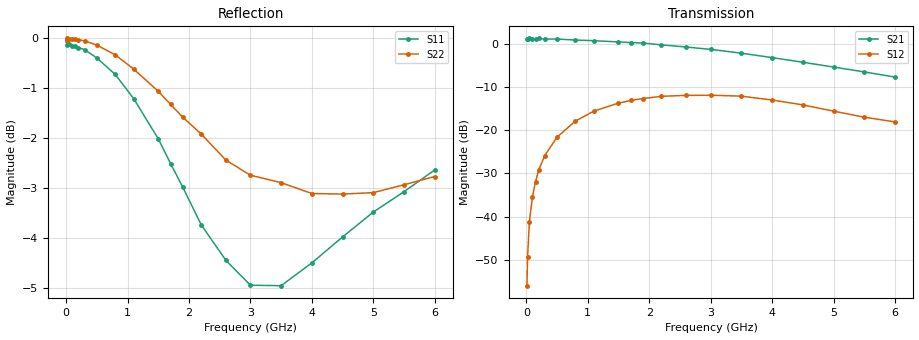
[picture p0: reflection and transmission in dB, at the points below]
! SIEMENS Small Signal Semiconductors
! BFP181
! Si NPN RF Bipolar Junction Transistor in SOT143
! VCE = 1 V  IC = 0.3 mA
! Common Emitter S-Parameters:  March  1996
# GHz  S  MA  R  50
!  f  S11  S21  S12  S22
! GHz  MAG  ANG  MAG  ANG  MAG  ANG  MAG  ANG
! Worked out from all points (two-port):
!   36 points, 10 MHz to 6 GHz, reference 50 ohm
!   highest |S21| = 1.21 dB at 50 MHz (marker M1); lowest = -7.7 dB at 6 GHz (marker M2)
!   |S21| within 3 dB of the highest: start of sweep to 3.259 GHz
!   lowest |S11| = -4.9 dB at 3.5 GHz (marker M3), VSWR 3.61, Z = 14.2 + j7.21 ohm
!   |S11| at or under -10 dB: nowhere
!   |S22| runs from -3.1 to 0.0 dB; largest |S21 - S12| = 1.1
!   S11 on the Smith chart (normalised r, x): 10 MHz: open; 800 MHz: 0.33, -2.63; 1.7 GHz: 0.28, -0.97; 2.6 GHz: 0.27, -0.30; 4 GHz: 0.28, +0.34; 6 GHz: 0.31, +0.99
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0.01  0.984 -0.5  1.132 179.9  0.0016 90.5  0.9999 -0.3
0.02  0.9947 -1.0  1.135 179.8  0.0034 95.3  0.9966 -0.5
0.05  0.9868 -2.4  1.149 177.3  0.0088 88.8  0.9985 -1.4
0.1  0.9814 -5.2  1.133 174.7  0.017 86.4  0.9981 -2.6
0.15  0.9822 -7.6  1.134 171.9  0.0254 83.9  0.9979 -3.9
0.2  0.9789 -10.2  1.146 169.2  0.0345 82.7  0.9968 -5.3
0.3  0.9743 -15.5  1.127 164.3  0.0509 78.5  0.9943 -8.0
0.5  0.9558 -25.8  1.128 152.3  0.0832 70.5  0.9846 -13.2
0.8  0.9202 -41.1  1.099 137.3  0.1275 59.3  0.9627 -20.8
1.1  0.8703 -56.8  1.08 122.0  0.1663 48.3  0.9316 -28.1
1.5  0.7935 -78.3  1.045 103.1  0.2054 34.7  0.8852 -37.0
1.7  0.7495 -89.5  1.028 94.0  0.2203 28.5  0.8589 -41.1
1.9  0.7096 -101.6  1.015 84.9  0.2322 22.4  0.8338 -45.0
2.2  0.6508 -118.7  0.967 71.4  0.2461 14.0  0.8021 -50.4
2.6  0.5998 -144.1  0.913 56.0  0.2523 3.7  0.7555 -57.1
3  0.5663 -168.8  0.857 40.3  0.2534 -6.8  0.7296 -64.0
3.5  0.5657 162.2  0.775 22.9  0.2473 -17.6  0.7172 -72.4
4  0.5962 139.5  0.689 7.8  0.2229 -27.1  0.6995 -82.4
4.5  0.6329 121.2  0.609 -5.0  0.196 -34.8  0.6986 -93.3
5  0.6702 107.3  0.536 -14.9  0.1658 -39.4  0.7009 -104.5
5.5  0.7024 96.3  0.471 -24.3  0.1414 -38.8  0.7137 -115.8
6  0.7384 87.7  0.411 -31.6  0.1247 -34.7  0.7274 -127.4
